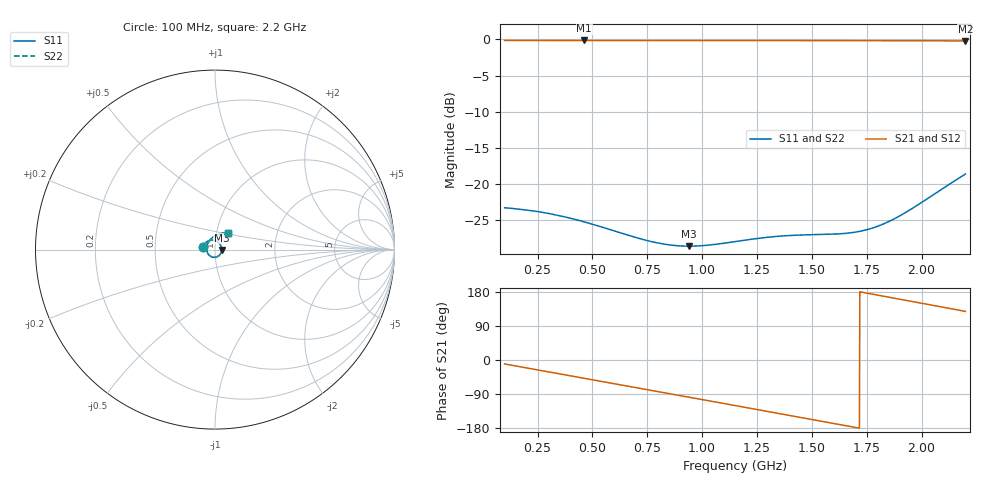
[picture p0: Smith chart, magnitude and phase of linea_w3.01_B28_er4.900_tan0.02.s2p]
! Chirptenna · simulación 3D de una microstrip de dos puertos (S12 = S21, S22 = S11 por simetría)
# HZ S RI R 50
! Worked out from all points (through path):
!   1101 points, 100 MHz to 2.2 GHz, reference 50 ohm
!   highest |S21| = -0.16 dB at 462.7 MHz (marker M1); lowest = -0.2 dB at 2.2 GHz (marker M2)
!   group delay of S21, straight-line fit = 292 ps
!   lowest |S11| = -28.6 dB at 940 MHz (marker M3), VSWR 1.08, Z = 53.9 - j0.166 ohm
!   |S11| at or under -10 dB: start of sweep to end of sweep
!   |S22| runs from -28.6 to -18.6 dB; largest |S21 - S12| = 0
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1e8  -0.0665 0.0171  0.9657 -0.1776  0.9657 -0.1776  -0.0665 0.0171
1.820909e8  -0.0596 0.0301  0.9286 -0.3192  0.9286 -0.3192  -0.0596 0.0301
2.699091e8  -0.0488 0.0414  0.8661 -0.4629  0.8661 -0.4629  -0.0488 0.0414
3.596364e8  -0.0348 0.0491  0.7794 -0.5975  0.7794 -0.5975  -0.0348 0.0491
4.512727e8  -0.0186 0.0523  0.6694 -0.7187  0.6694 -0.7187  -0.0186 0.0523
4.627273e8  -0.0166 0.0524  0.6542 -0.7325  0.6542 -0.7325  -0.0166 0.0524
6.364545e8  0.0131 0.0438  0.3936 -0.8997  0.3936 -0.8997  0.0131 0.0438
8.006364e8  0.0324 0.0221  0.1105 -0.9756  0.1105 -0.9756  0.0324 0.0221
9.4e8  0.0373 -0.00154  -0.1387 -0.9717  -0.1387 -0.9717  0.0373 -0.00154
1.043091e9  0.0333 -0.0186  -0.3182 -0.9283  -0.3182 -0.9283  0.0333 -0.0186
1.15e9  0.0229 -0.0329  -0.4924 -0.8485  -0.4924 -0.8485  0.0229 -0.0329
1.239727e9  0.0104 -0.0406  -0.6245 -0.7564  -0.6245 -0.7564  0.0104 -0.0406
1.333273e9  -0.00476 -0.0432  -0.7443 -0.6386  -0.7443 -0.6386  -0.00476 -0.0432
1.501273e9  -0.0312 -0.0321  -0.9031 -0.3821  -0.9031 -0.3821  -0.0312 -0.0321
1.589091e9  -0.0412 -0.0185  -0.9529 -0.2315  -0.9529 -0.2315  -0.0412 -0.0185
1.676909e9  -0.0462 -0.0005  -0.9777 -0.0744  -0.9777 -0.0744  -0.0462 -0.0005
1.764727e9  -0.0448 0.0203  -0.9767 0.0852  -0.9767 0.0852  -0.0448 0.0203
1.850636e9  -0.0362 0.0416  -0.9504 0.2396  -0.9504 0.2396  -0.0362 0.0416
1.932727e9  -0.0209 0.0609  -0.9021 0.3816  -0.9021 0.3816  -0.0209 0.0609
2.014818e9  0.00118 0.0772  -0.8321 0.5148  -0.8321 0.5148  0.00118 0.0772
2.117909e9  0.0376 0.0904  -0.7159 0.6639  -0.7159 0.6639  0.0376 0.0904
2.2e9  0.0718 0.0929  -0.6036 0.7645  -0.6036 0.7645  0.0718 0.0929
